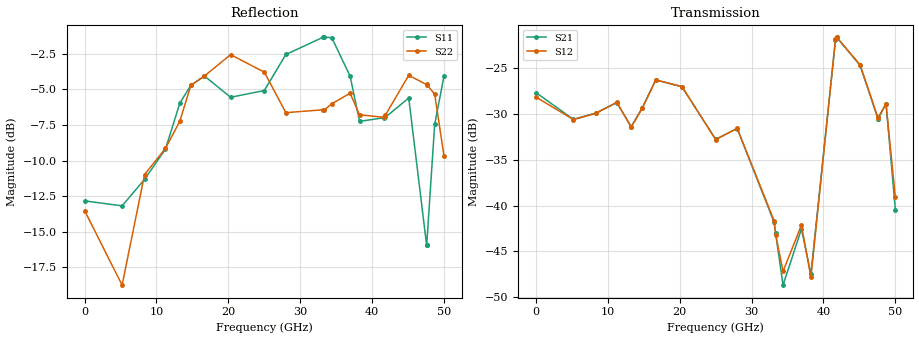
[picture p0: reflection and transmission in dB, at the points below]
!Keysight Technologies,N5245B,MY58422270,A.16.20.02
!Date: Thursday, March 05, 2026 01:39:10
!Correction: S11(C  2-Port  )
!S21(C  2-Port  )
!S12(C  2-Port  )
!S22(C  2-Port  )
!S2P File: Measurements: S11, S21, S12, S22:
# Hz S  dB  R 50
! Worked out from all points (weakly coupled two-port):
!   3201 points, 10 MHz to 50 GHz, reference 50 ohm
!   highest |S21| = -21.62 dB at 41.86 GHz (marker M1); lowest = -48.7 dB at 34.38 GHz (marker M2)
!   lowest |S11| = -15.9 dB at 47.58 GHz (marker M3), VSWR 1.38, Z = 45.2 + j14.6 ohm
!   |S11| at or under -10 dB: start of sweep to 9.792 GHz; 11.44 GHz to 11.87 GHz (421.5 MHz wide, 3.62 % of centre); 46.75 GHz to 48.32 GHz (1.566 GHz wide, 3.29 % of centre)
!   |S22| runs from -18.8 to -2.5 dB; largest |S21 - S12| = 0.0032
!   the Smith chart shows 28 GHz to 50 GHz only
!   S11 on the Smith chart (normalised r, x): 28 GHz: 0.20, +0.57; 33.14 GHz: 0.67, +2.68; 36.94 GHz: 1.52, -1.91; 47.59 GHz: 0.92, +0.30; 50 GHz: 0.54, -1.09
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1e7  -12.83 -4.5  -27.64 3.6  -28.13 6.8  -13.51 35.5
5.227706e9  -13.18 -130.1  -30.57 163.1  -30.59 163.0  -18.74 -135.1
8.352081e9  -11.32 170.3  -29.87 31.9  -29.92 31.8  -10.98 -161.4
1.125775e10  -9.20 99.5  -28.73 -72.2  -28.70 -72.5  -9.15 88.0
1.325735e10  -5.97 59.9  -31.36 -119.8  -31.42 -120.0  -7.24 -20.8
1.478829e10  -4.72 12.5  -29.33 -147.1  -29.37 -147.3  -4.73 -89.9
1.667854e10  -4.07 -44.4  -26.26 158.5  -26.26 158.2  -4.07 -141.8
2.031844e10  -5.56 -126.6  -27.00 39.9  -26.99 39.8  -2.57 153.8
2.5005e10  -5.09 171.4  -32.75 -68.1  -32.77 -68.1  -3.80 70.6
2.80044e10  -2.56 118.9  -31.57 -132.8  -31.55 -132.9  -6.64 16.1
3.3144e10  -1.36 38.9  -41.83 12.1  -41.67 8.3  -6.44 -126.3
3.334708e10  -1.36 35.5  -43.01 -0.2  -43.15 -2.6  -6.46 -130.9
3.437812e10  -1.37 17.7  -48.68 -99.0  -47.18 -101.6  -6.02 -153.5
3.694011e10  -4.08 -37.6  -42.55 94.9  -42.13 92.9  -5.28 156.3
3.825235e10  -7.25 -20.5  -47.47 95.3  -47.83 92.2  -6.79 133.9
4.167354e10  -7.00 -56.5  -21.89 -61.0  -21.77 -61.3  -6.97 113.3
4.1861e10  -6.96 -56.5  -21.62 -78.9  -21.61 -78.9  -6.80 112.2
4.509473e10  -5.61 -105.8  -24.66 87.4  -24.61 86.8  -4.02 75.6
4.757861e10  -15.93 99.4  -30.53 -15.2  -30.38 -14.6  -4.67 42.1
4.759423e10  -15.92 96.6  -30.52 -15.2  -30.34 -14.7  -4.66 41.9
4.870338e10  -7.46 -25.6  -28.85 -90.1  -28.90 -90.3  -5.34 20.0
5e10  -4.07 -77.8  -40.47 -142.3  -39.10 -145.2  -9.69 6.5
